VERSION 5.7 ;
BUSBITCHARS "[]" ;
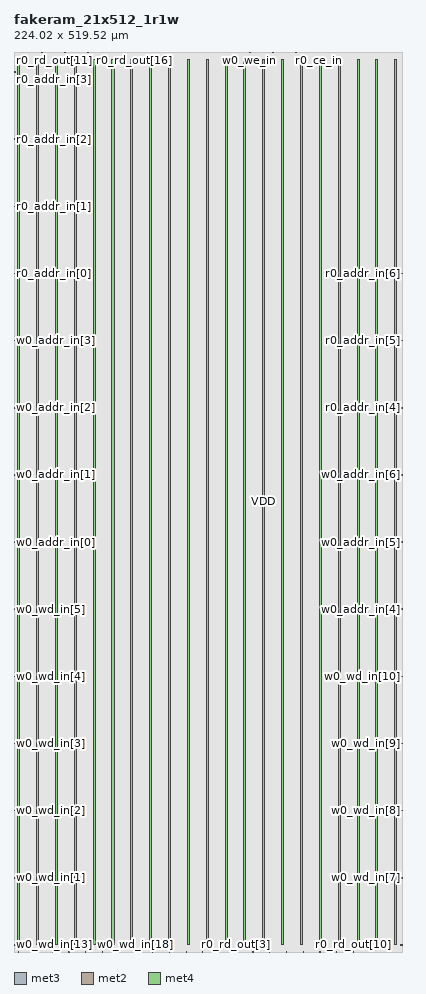
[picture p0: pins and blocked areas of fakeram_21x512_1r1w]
MACRO fakeram_21x512_1r1w
  FOREIGN fakeram_21x512_1r1w 0 0 ;
  SYMMETRY X Y R90 ;
  SIZE 224.020 BY 519.520 ;
  CLASS BLOCK ;
  PIN w0_wd_in[0]
    DIRECTION INPUT ;
    USE SIGNAL ;
    SHAPE ABUTMENT ;
    PORT
      LAYER met3 ;
      RECT 0.000 3.930 0.900 4.230 ;
    END
  END w0_wd_in[0]
  PIN w0_wd_in[1]
    DIRECTION INPUT ;
    USE SIGNAL ;
    SHAPE ABUTMENT ;
    PORT
      LAYER met3 ;
      RECT 0.000 42.690 0.900 42.990 ;
    END
  END w0_wd_in[1]
  PIN w0_wd_in[2]
    DIRECTION INPUT ;
    USE SIGNAL ;
    SHAPE ABUTMENT ;
    PORT
      LAYER met3 ;
      RECT 0.000 81.450 0.900 81.750 ;
    END
  END w0_wd_in[2]
  PIN w0_wd_in[3]
    DIRECTION INPUT ;
    USE SIGNAL ;
    SHAPE ABUTMENT ;
    PORT
      LAYER met3 ;
      RECT 0.000 120.210 0.900 120.510 ;
    END
  END w0_wd_in[3]
  PIN w0_wd_in[4]
    DIRECTION INPUT ;
    USE SIGNAL ;
    SHAPE ABUTMENT ;
    PORT
      LAYER met3 ;
      RECT 0.000 158.970 0.900 159.270 ;
    END
  END w0_wd_in[4]
  PIN w0_wd_in[5]
    DIRECTION INPUT ;
    USE SIGNAL ;
    SHAPE ABUTMENT ;
    PORT
      LAYER met3 ;
      RECT 0.000 197.730 0.900 198.030 ;
    END
  END w0_wd_in[5]
  PIN w0_wd_in[6]
    DIRECTION INPUT ;
    USE SIGNAL ;
    SHAPE ABUTMENT ;
    PORT
      LAYER met3 ;
      RECT 223.120 3.930 224.020 4.230 ;
    END
  END w0_wd_in[6]
  PIN w0_wd_in[7]
    DIRECTION INPUT ;
    USE SIGNAL ;
    SHAPE ABUTMENT ;
    PORT
      LAYER met3 ;
      RECT 223.120 42.690 224.020 42.990 ;
    END
  END w0_wd_in[7]
  PIN w0_wd_in[8]
    DIRECTION INPUT ;
    USE SIGNAL ;
    SHAPE ABUTMENT ;
    PORT
      LAYER met3 ;
      RECT 223.120 81.450 224.020 81.750 ;
    END
  END w0_wd_in[8]
  PIN w0_wd_in[9]
    DIRECTION INPUT ;
    USE SIGNAL ;
    SHAPE ABUTMENT ;
    PORT
      LAYER met3 ;
      RECT 223.120 120.210 224.020 120.510 ;
    END
  END w0_wd_in[9]
  PIN w0_wd_in[10]
    DIRECTION INPUT ;
    USE SIGNAL ;
    SHAPE ABUTMENT ;
    PORT
      LAYER met3 ;
      RECT 223.120 158.970 224.020 159.270 ;
    END
  END w0_wd_in[10]
  PIN w0_wd_in[11]
    DIRECTION OUTPUT ;
    USE SIGNAL ;
    SHAPE ABUTMENT ;
    PORT
      LAYER met2 ;
      RECT 2.690 0.000 2.830 0.420 ;
    END
  END w0_wd_in[11]
  PIN w0_wd_in[12]
    DIRECTION OUTPUT ;
    USE SIGNAL ;
    SHAPE ABUTMENT ;
    PORT
      LAYER met2 ;
      RECT 12.350 0.000 12.490 0.420 ;
    END
  END w0_wd_in[12]
  PIN w0_wd_in[13]
    DIRECTION OUTPUT ;
    USE SIGNAL ;
    SHAPE ABUTMENT ;
    PORT
      LAYER met2 ;
      RECT 22.010 0.000 22.150 0.420 ;
    END
  END w0_wd_in[13]
  PIN w0_wd_in[14]
    DIRECTION OUTPUT ;
    USE SIGNAL ;
    SHAPE ABUTMENT ;
    PORT
      LAYER met2 ;
      RECT 31.670 0.000 31.810 0.420 ;
    END
  END w0_wd_in[14]
  PIN w0_wd_in[15]
    DIRECTION OUTPUT ;
    USE SIGNAL ;
    SHAPE ABUTMENT ;
    PORT
      LAYER met2 ;
      RECT 41.330 0.000 41.470 0.420 ;
    END
  END w0_wd_in[15]
  PIN w0_wd_in[16]
    DIRECTION OUTPUT ;
    USE SIGNAL ;
    SHAPE ABUTMENT ;
    PORT
      LAYER met2 ;
      RECT 50.990 0.000 51.130 0.420 ;
    END
  END w0_wd_in[16]
  PIN w0_wd_in[17]
    DIRECTION OUTPUT ;
    USE SIGNAL ;
    SHAPE ABUTMENT ;
    PORT
      LAYER met2 ;
      RECT 60.650 0.000 60.790 0.420 ;
    END
  END w0_wd_in[17]
  PIN w0_wd_in[18]
    DIRECTION OUTPUT ;
    USE SIGNAL ;
    SHAPE ABUTMENT ;
    PORT
      LAYER met2 ;
      RECT 70.310 0.000 70.450 0.420 ;
    END
  END w0_wd_in[18]
  PIN w0_wd_in[19]
    DIRECTION OUTPUT ;
    USE SIGNAL ;
    SHAPE ABUTMENT ;
    PORT
      LAYER met2 ;
      RECT 79.970 0.000 80.110 0.420 ;
    END
  END w0_wd_in[19]
  PIN w0_wd_in[20]
    DIRECTION OUTPUT ;
    USE SIGNAL ;
    SHAPE ABUTMENT ;
    PORT
      LAYER met2 ;
      RECT 89.630 0.000 89.770 0.420 ;
    END
  END w0_wd_in[20]
  PIN r0_rd_out[0]
    DIRECTION OUTPUT ;
    USE SIGNAL ;
    SHAPE ABUTMENT ;
    PORT
      LAYER met2 ;
      RECT 99.290 0.000 99.430 0.420 ;
    END
  END r0_rd_out[0]
  PIN r0_rd_out[1]
    DIRECTION OUTPUT ;
    USE SIGNAL ;
    SHAPE ABUTMENT ;
    PORT
      LAYER met2 ;
      RECT 108.950 0.000 109.090 0.420 ;
    END
  END r0_rd_out[1]
  PIN r0_rd_out[2]
    DIRECTION OUTPUT ;
    USE SIGNAL ;
    SHAPE ABUTMENT ;
    PORT
      LAYER met2 ;
      RECT 118.610 0.000 118.750 0.420 ;
    END
  END r0_rd_out[2]
  PIN r0_rd_out[3]
    DIRECTION OUTPUT ;
    USE SIGNAL ;
    SHAPE ABUTMENT ;
    PORT
      LAYER met2 ;
      RECT 128.270 0.000 128.410 0.420 ;
    END
  END r0_rd_out[3]
  PIN r0_rd_out[4]
    DIRECTION OUTPUT ;
    USE SIGNAL ;
    SHAPE ABUTMENT ;
    PORT
      LAYER met2 ;
      RECT 137.930 0.000 138.070 0.420 ;
    END
  END r0_rd_out[4]
  PIN r0_rd_out[5]
    DIRECTION OUTPUT ;
    USE SIGNAL ;
    SHAPE ABUTMENT ;
    PORT
      LAYER met2 ;
      RECT 147.590 0.000 147.730 0.420 ;
    END
  END r0_rd_out[5]
  PIN r0_rd_out[6]
    DIRECTION OUTPUT ;
    USE SIGNAL ;
    SHAPE ABUTMENT ;
    PORT
      LAYER met2 ;
      RECT 157.250 0.000 157.390 0.420 ;
    END
  END r0_rd_out[6]
  PIN r0_rd_out[7]
    DIRECTION OUTPUT ;
    USE SIGNAL ;
    SHAPE ABUTMENT ;
    PORT
      LAYER met2 ;
      RECT 166.910 0.000 167.050 0.420 ;
    END
  END r0_rd_out[7]
  PIN r0_rd_out[8]
    DIRECTION OUTPUT ;
    USE SIGNAL ;
    SHAPE ABUTMENT ;
    PORT
      LAYER met2 ;
      RECT 176.570 0.000 176.710 0.420 ;
    END
  END r0_rd_out[8]
  PIN r0_rd_out[9]
    DIRECTION OUTPUT ;
    USE SIGNAL ;
    SHAPE ABUTMENT ;
    PORT
      LAYER met2 ;
      RECT 186.230 0.000 186.370 0.420 ;
    END
  END r0_rd_out[9]
  PIN r0_rd_out[10]
    DIRECTION OUTPUT ;
    USE SIGNAL ;
    SHAPE ABUTMENT ;
    PORT
      LAYER met2 ;
      RECT 195.890 0.000 196.030 0.420 ;
    END
  END r0_rd_out[10]
  PIN r0_rd_out[11]
    DIRECTION OUTPUT ;
    USE SIGNAL ;
    SHAPE ABUTMENT ;
    PORT
      LAYER met2 ;
      RECT 2.690 519.100 2.830 519.520 ;
    END
  END r0_rd_out[11]
  PIN r0_rd_out[12]
    DIRECTION OUTPUT ;
    USE SIGNAL ;
    SHAPE ABUTMENT ;
    PORT
      LAYER met2 ;
      RECT 16.030 519.100 16.170 519.520 ;
    END
  END r0_rd_out[12]
  PIN r0_rd_out[13]
    DIRECTION OUTPUT ;
    USE SIGNAL ;
    SHAPE ABUTMENT ;
    PORT
      LAYER met2 ;
      RECT 29.370 519.100 29.510 519.520 ;
    END
  END r0_rd_out[13]
  PIN r0_rd_out[14]
    DIRECTION OUTPUT ;
    USE SIGNAL ;
    SHAPE ABUTMENT ;
    PORT
      LAYER met2 ;
      RECT 42.710 519.100 42.850 519.520 ;
    END
  END r0_rd_out[14]
  PIN r0_rd_out[15]
    DIRECTION OUTPUT ;
    USE SIGNAL ;
    SHAPE ABUTMENT ;
    PORT
      LAYER met2 ;
      RECT 56.050 519.100 56.190 519.520 ;
    END
  END r0_rd_out[15]
  PIN r0_rd_out[16]
    DIRECTION OUTPUT ;
    USE SIGNAL ;
    SHAPE ABUTMENT ;
    PORT
      LAYER met2 ;
      RECT 69.390 519.100 69.530 519.520 ;
    END
  END r0_rd_out[16]
  PIN r0_rd_out[17]
    DIRECTION OUTPUT ;
    USE SIGNAL ;
    SHAPE ABUTMENT ;
    PORT
      LAYER met2 ;
      RECT 82.730 519.100 82.870 519.520 ;
    END
  END r0_rd_out[17]
  PIN r0_rd_out[18]
    DIRECTION OUTPUT ;
    USE SIGNAL ;
    SHAPE ABUTMENT ;
    PORT
      LAYER met2 ;
      RECT 96.070 519.100 96.210 519.520 ;
    END
  END r0_rd_out[18]
  PIN r0_rd_out[19]
    DIRECTION OUTPUT ;
    USE SIGNAL ;
    SHAPE ABUTMENT ;
    PORT
      LAYER met2 ;
      RECT 109.410 519.100 109.550 519.520 ;
    END
  END r0_rd_out[19]
  PIN r0_rd_out[20]
    DIRECTION OUTPUT ;
    USE SIGNAL ;
    SHAPE ABUTMENT ;
    PORT
      LAYER met2 ;
      RECT 122.750 519.100 122.890 519.520 ;
    END
  END r0_rd_out[20]
  PIN w0_addr_in[0]
    DIRECTION INPUT ;
    USE SIGNAL ;
    SHAPE ABUTMENT ;
    PORT
      LAYER met3 ;
      RECT 0.000 236.490 0.900 236.790 ;
    END
  END w0_addr_in[0]
  PIN w0_addr_in[1]
    DIRECTION INPUT ;
    USE SIGNAL ;
    SHAPE ABUTMENT ;
    PORT
      LAYER met3 ;
      RECT 0.000 275.250 0.900 275.550 ;
    END
  END w0_addr_in[1]
  PIN w0_addr_in[2]
    DIRECTION INPUT ;
    USE SIGNAL ;
    SHAPE ABUTMENT ;
    PORT
      LAYER met3 ;
      RECT 0.000 314.010 0.900 314.310 ;
    END
  END w0_addr_in[2]
  PIN w0_addr_in[3]
    DIRECTION INPUT ;
    USE SIGNAL ;
    SHAPE ABUTMENT ;
    PORT
      LAYER met3 ;
      RECT 0.000 352.770 0.900 353.070 ;
    END
  END w0_addr_in[3]
  PIN w0_addr_in[4]
    DIRECTION INPUT ;
    USE SIGNAL ;
    SHAPE ABUTMENT ;
    PORT
      LAYER met3 ;
      RECT 223.120 197.730 224.020 198.030 ;
    END
  END w0_addr_in[4]
  PIN w0_addr_in[5]
    DIRECTION INPUT ;
    USE SIGNAL ;
    SHAPE ABUTMENT ;
    PORT
      LAYER met3 ;
      RECT 223.120 236.490 224.020 236.790 ;
    END
  END w0_addr_in[5]
  PIN w0_addr_in[6]
    DIRECTION INPUT ;
    USE SIGNAL ;
    SHAPE ABUTMENT ;
    PORT
      LAYER met3 ;
      RECT 223.120 275.250 224.020 275.550 ;
    END
  END w0_addr_in[6]
  PIN r0_addr_in[0]
    DIRECTION INPUT ;
    USE SIGNAL ;
    SHAPE ABUTMENT ;
    PORT
      LAYER met3 ;
      RECT 0.000 391.530 0.900 391.830 ;
    END
  END r0_addr_in[0]
  PIN r0_addr_in[1]
    DIRECTION INPUT ;
    USE SIGNAL ;
    SHAPE ABUTMENT ;
    PORT
      LAYER met3 ;
      RECT 0.000 430.290 0.900 430.590 ;
    END
  END r0_addr_in[1]
  PIN r0_addr_in[2]
    DIRECTION INPUT ;
    USE SIGNAL ;
    SHAPE ABUTMENT ;
    PORT
      LAYER met3 ;
      RECT 0.000 469.050 0.900 469.350 ;
    END
  END r0_addr_in[2]
  PIN r0_addr_in[3]
    DIRECTION INPUT ;
    USE SIGNAL ;
    SHAPE ABUTMENT ;
    PORT
      LAYER met3 ;
      RECT 0.000 507.810 0.900 508.110 ;
    END
  END r0_addr_in[3]
  PIN r0_addr_in[4]
    DIRECTION INPUT ;
    USE SIGNAL ;
    SHAPE ABUTMENT ;
    PORT
      LAYER met3 ;
      RECT 223.120 314.010 224.020 314.310 ;
    END
  END r0_addr_in[4]
  PIN r0_addr_in[5]
    DIRECTION INPUT ;
    USE SIGNAL ;
    SHAPE ABUTMENT ;
    PORT
      LAYER met3 ;
      RECT 223.120 352.770 224.020 353.070 ;
    END
  END r0_addr_in[5]
  PIN r0_addr_in[6]
    DIRECTION INPUT ;
    USE SIGNAL ;
    SHAPE ABUTMENT ;
    PORT
      LAYER met3 ;
      RECT 223.120 391.530 224.020 391.830 ;
    END
  END r0_addr_in[6]
  PIN w0_we_in
    DIRECTION INPUT ;
    USE SIGNAL ;
    SHAPE ABUTMENT ;
    PORT
      LAYER met2 ;
      RECT 136.090 519.100 136.230 519.520 ;
    END
  END w0_we_in
  PIN w0_ce_in
    DIRECTION INPUT ;
    USE SIGNAL ;
    SHAPE ABUTMENT ;
    PORT
      LAYER met2 ;
      RECT 149.430 519.100 149.570 519.520 ;
    END
  END w0_ce_in
  PIN w0_clk
    DIRECTION INPUT ;
    USE SIGNAL ;
    SHAPE ABUTMENT ;
    PORT
      LAYER met2 ;
      RECT 162.770 519.100 162.910 519.520 ;
    END
  END w0_clk
  PIN r0_ce_in
    DIRECTION INPUT ;
    USE SIGNAL ;
    SHAPE ABUTMENT ;
    PORT
      LAYER met2 ;
      RECT 176.110 519.100 176.250 519.520 ;
    END
  END r0_ce_in
  PIN r0_clk
    DIRECTION INPUT ;
    USE SIGNAL ;
    SHAPE ABUTMENT ;
    PORT
      LAYER met2 ;
      RECT 189.450 519.100 189.590 519.520 ;
    END
  END r0_clk
  PIN VSS
    DIRECTION INOUT ;
    USE GROUND ;
    PORT
      LAYER met4 ;
      RECT 2.160 4.080 3.360 515.440 ;
      RECT 13.040 4.080 14.240 515.440 ;
      RECT 23.920 4.080 25.120 515.440 ;
      RECT 34.800 4.080 36.000 515.440 ;
      RECT 45.680 4.080 46.880 515.440 ;
      RECT 56.560 4.080 57.760 515.440 ;
      RECT 67.440 4.080 68.640 515.440 ;
      RECT 78.320 4.080 79.520 515.440 ;
      RECT 89.200 4.080 90.400 515.440 ;
      RECT 100.080 4.080 101.280 515.440 ;
      RECT 110.960 4.080 112.160 515.440 ;
      RECT 121.840 4.080 123.040 515.440 ;
      RECT 132.720 4.080 133.920 515.440 ;
      RECT 143.600 4.080 144.800 515.440 ;
      RECT 154.480 4.080 155.680 515.440 ;
      RECT 165.360 4.080 166.560 515.440 ;
      RECT 176.240 4.080 177.440 515.440 ;
      RECT 187.120 4.080 188.320 515.440 ;
      RECT 198.000 4.080 199.200 515.440 ;
      RECT 208.880 4.080 210.080 515.440 ;
      RECT 219.760 4.080 220.960 515.440 ;
    END
  END VSS
  PIN VDD
    DIRECTION INOUT ;
    USE POWER ;
    PORT
      LAYER met4 ;
      RECT 2.160 4.080 3.360 515.440 ;
      RECT 13.040 4.080 14.240 515.440 ;
      RECT 23.920 4.080 25.120 515.440 ;
      RECT 34.800 4.080 36.000 515.440 ;
      RECT 45.680 4.080 46.880 515.440 ;
      RECT 56.560 4.080 57.760 515.440 ;
      RECT 67.440 4.080 68.640 515.440 ;
      RECT 78.320 4.080 79.520 515.440 ;
      RECT 89.200 4.080 90.400 515.440 ;
      RECT 100.080 4.080 101.280 515.440 ;
      RECT 110.960 4.080 112.160 515.440 ;
      RECT 121.840 4.080 123.040 515.440 ;
      RECT 132.720 4.080 133.920 515.440 ;
      RECT 143.600 4.080 144.800 515.440 ;
      RECT 154.480 4.080 155.680 515.440 ;
      RECT 165.360 4.080 166.560 515.440 ;
      RECT 176.240 4.080 177.440 515.440 ;
      RECT 187.120 4.080 188.320 515.440 ;
      RECT 198.000 4.080 199.200 515.440 ;
      RECT 208.880 4.080 210.080 515.440 ;
      RECT 219.760 4.080 220.960 515.440 ;
    END
  END VDD
  OBS
    LAYER met1 ;
    RECT 0 0 224.020 519.520 ;
    LAYER met2 ;
    RECT 0 0 224.020 519.520 ;
    LAYER met3 ;
    RECT 0 0 224.020 519.520 ;
    LAYER met4 ;
    RECT 0 0 224.020 519.520 ;
  END
END fakeram_21x512_1r1w

END LIBRARY
